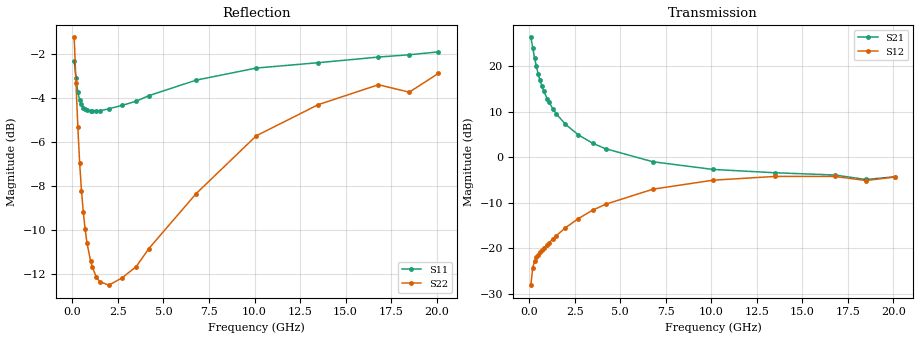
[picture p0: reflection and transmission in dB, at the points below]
!  Infineon Technologies AG
! BFR380L3 , PF131585-7, No.6, Th 09.10.01, soldered on pcb-board, measured with PP GSG850
!  Vce=0.5 V,  Ic=7.5 mA
! Common Emitter S-Parameters:  15. November 2001
#  GHz  S  MA  R  50
! f  S11  S21  S12  S22
! GHz  Mag  Ang  Mag  Ang  Mag  Ang  Mag  Ang
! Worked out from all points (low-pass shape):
!   201 points, 100 MHz to 20.1 GHz, reference 50 ohm
!   highest |S21| = 26.36 dB at 100 MHz (marker M1); lowest = -4.9 dB at 18.5 GHz (marker M2)
!   |S21| within 3 dB of the highest: start of sweep to 233.1 MHz
!   lowest |S11| = -4.6 dB at 1.1 GHz (marker M3), VSWR 3.85, Z = 13 - j3.2 ohm
!   |S11| at or under -10 dB: nowhere
!   |S22| runs from -12.5 to -1.3 dB; largest |S21 - S12| = 21
!   S11 on the Smith chart (normalised r, x): 100 MHz: 0.68, -1.94; 300 MHz: 0.31, -0.64; 1 GHz: 0.26, -0.09; 4.2 GHz: 0.27, +0.43; 10.1 GHz: 0.38, +1.20; 20.1 GHz: 0.92, +2.57
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0.1  0.7655 -50.3  20.81 150.0  0.03934 65.1  0.8643 -34.9
0.2  0.6974 -86.8  16.02 129.6  0.06107 51.5  0.6792 -59.8
0.3  0.6494 -110.9  12.43 117.2  0.0723 45.0  0.54 -76.5
0.4  0.6234 -126.8  9.97 108.7  0.0794 41.9  0.4482 -88.8
0.5  0.6091 -138.3  8.26 102.6  0.0848 41.1  0.3877 -98.5
0.6  0.5985 -147.1  7.025 97.9  0.08993 41.3  0.3464 -106.5
0.7  0.5954 -154.1  6.115 93.9  0.0947 41.8  0.3169 -113.4
0.8  0.5909 -159.6  5.401 90.5  0.09979 42.6  0.2954 -119.2
1  0.5881 -168.6  4.388 84.9  0.1099 44.5  0.2682 -128.9
1.1  0.5878 -172.1  4.015 82.4  0.1153 45.3  0.26 -133.0
1.3  0.5893 -178.6  3.43 77.8  0.1261 46.9  0.2476 -140.1
1.5  0.589 176.0  3.002 73.7  0.1378 48.0  0.241 -145.8
2  0.5949 165.1  2.302 64.5  0.168 49.4  0.2367 -156.9
2.7  0.6054 152.2  1.769 53.4  0.2117 49.2  0.2454 -168.7
3.5  0.619 139.8  1.425 42.3  0.2627 46.6  0.2606 -178.4
4.2  0.6374 130.5  1.243 34.0  0.3044 43.6  0.2866 173.1
6.8  0.6912 101.4  0.8932 10.1  0.4462 27.7  0.3821 145.5
10.1  0.7363 76.3  0.7356 -8.5  0.5602 7.0  0.5168 117.2
13.5  0.7572 59.3  0.6765 -23.0  0.6162 -12.7  0.6081 92.1
16.8  0.7798 47.4  0.6383 -34.0  0.616 -27.6  0.6747 72.9
18.5  0.7892 45.4  0.5702 -41.2  0.5555 -35.8  0.6491 68.0
20.1  0.8012 38.5  0.6111 -44.6  0.6075 -40.4  0.7162 58.0
